VERSION 5.7 ;
  NOWIREEXTENSIONATPIN ON ;
  DIVIDERCHAR "/" ;
  BUSBITCHARS "[]" ;
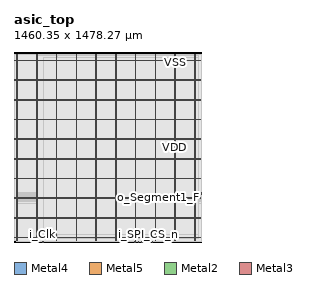
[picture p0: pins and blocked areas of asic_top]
MACRO asic_top
  CLASS BLOCK ;
  FOREIGN asic_top ;
  ORIGIN 0.000 0.000 ;
  SIZE 1460.350 BY 1478.270 ;
  PIN VDD
    DIRECTION INOUT ;
    USE POWER ;
    PORT
      LAYER Metal4 ;
        RECT 22.240 15.380 23.840 1462.460 ;
    END
    PORT
      LAYER Metal4 ;
        RECT 175.840 15.380 177.440 1462.460 ;
    END
    PORT
      LAYER Metal4 ;
        RECT 329.440 15.380 331.040 1462.460 ;
    END
    PORT
      LAYER Metal4 ;
        RECT 483.040 15.380 484.640 1462.460 ;
    END
    PORT
      LAYER Metal4 ;
        RECT 636.640 15.380 638.240 1462.460 ;
    END
    PORT
      LAYER Metal4 ;
        RECT 790.240 15.380 791.840 1462.460 ;
    END
    PORT
      LAYER Metal4 ;
        RECT 943.840 15.380 945.440 1462.460 ;
    END
    PORT
      LAYER Metal4 ;
        RECT 1097.440 15.380 1099.040 1462.460 ;
    END
    PORT
      LAYER Metal4 ;
        RECT 1251.040 15.380 1252.640 1462.460 ;
    END
    PORT
      LAYER Metal4 ;
        RECT 1404.640 15.380 1406.240 1462.460 ;
    END
    PORT
      LAYER Metal5 ;
        RECT 6.720 31.530 1453.200 33.130 ;
    END
    PORT
      LAYER Metal5 ;
        RECT 6.720 184.710 1453.200 186.310 ;
    END
    PORT
      LAYER Metal5 ;
        RECT 6.720 337.890 1453.200 339.490 ;
    END
    PORT
      LAYER Metal5 ;
        RECT 6.720 491.070 1453.200 492.670 ;
    END
    PORT
      LAYER Metal5 ;
        RECT 6.720 644.250 1453.200 645.850 ;
    END
    PORT
      LAYER Metal5 ;
        RECT 6.720 797.430 1453.200 799.030 ;
    END
    PORT
      LAYER Metal5 ;
        RECT 6.720 950.610 1453.200 952.210 ;
    END
    PORT
      LAYER Metal5 ;
        RECT 6.720 1103.790 1453.200 1105.390 ;
    END
    PORT
      LAYER Metal5 ;
        RECT 6.720 1256.970 1453.200 1258.570 ;
    END
    PORT
      LAYER Metal5 ;
        RECT 6.720 1410.150 1453.200 1411.750 ;
    END
  END VDD
  PIN VSS
    DIRECTION INOUT ;
    USE GROUND ;
    PORT
      LAYER Metal4 ;
        RECT 25.540 15.380 27.140 1462.460 ;
    END
    PORT
      LAYER Metal4 ;
        RECT 179.140 15.380 180.740 1462.460 ;
    END
    PORT
      LAYER Metal4 ;
        RECT 332.740 15.380 334.340 1462.460 ;
    END
    PORT
      LAYER Metal4 ;
        RECT 486.340 15.380 487.940 1462.460 ;
    END
    PORT
      LAYER Metal4 ;
        RECT 639.940 15.380 641.540 1462.460 ;
    END
    PORT
      LAYER Metal4 ;
        RECT 793.540 15.380 795.140 1462.460 ;
    END
    PORT
      LAYER Metal4 ;
        RECT 947.140 15.380 948.740 1462.460 ;
    END
    PORT
      LAYER Metal4 ;
        RECT 1100.740 15.380 1102.340 1462.460 ;
    END
    PORT
      LAYER Metal4 ;
        RECT 1254.340 15.380 1255.940 1462.460 ;
    END
    PORT
      LAYER Metal4 ;
        RECT 1407.940 15.380 1409.540 1462.460 ;
    END
    PORT
      LAYER Metal5 ;
        RECT 6.720 34.830 1453.200 36.430 ;
    END
    PORT
      LAYER Metal5 ;
        RECT 6.720 188.010 1453.200 189.610 ;
    END
    PORT
      LAYER Metal5 ;
        RECT 6.720 341.190 1453.200 342.790 ;
    END
    PORT
      LAYER Metal5 ;
        RECT 6.720 494.370 1453.200 495.970 ;
    END
    PORT
      LAYER Metal5 ;
        RECT 6.720 647.550 1453.200 649.150 ;
    END
    PORT
      LAYER Metal5 ;
        RECT 6.720 800.730 1453.200 802.330 ;
    END
    PORT
      LAYER Metal5 ;
        RECT 6.720 953.910 1453.200 955.510 ;
    END
    PORT
      LAYER Metal5 ;
        RECT 6.720 1107.090 1453.200 1108.690 ;
    END
    PORT
      LAYER Metal5 ;
        RECT 6.720 1260.270 1453.200 1261.870 ;
    END
    PORT
      LAYER Metal5 ;
        RECT 6.720 1413.450 1453.200 1415.050 ;
    END
  END VSS
  PIN i_Clk
    DIRECTION INPUT ;
    USE SIGNAL ;
    ANTENNAGATEAREA 4.738000 ;
    PORT
      LAYER Metal2 ;
        RECT 225.120 0.000 225.680 0.560 ;
    END
  END i_Clk
  PIN i_SPI_CS_n
    DIRECTION INPUT ;
    USE SIGNAL ;
    ANTENNAGATEAREA 0.396000 ;
    PORT
      LAYER Metal2 ;
        RECT 1047.200 0.000 1047.760 0.560 ;
    END
  END i_SPI_CS_n
  PIN i_SPI_MOSI
    DIRECTION INPUT ;
    USE SIGNAL ;
    ANTENNAGATEAREA 0.396000 ;
    PORT
      LAYER Metal2 ;
        RECT 943.040 0.000 943.600 0.560 ;
    END
  END i_SPI_MOSI
  PIN i_SPI_SCLK
    DIRECTION INPUT ;
    USE SIGNAL ;
    ANTENNAGATEAREA 0.396000 ;
    PORT
      LAYER Metal2 ;
        RECT 1078.560 0.000 1079.120 0.560 ;
    END
  END i_SPI_SCLK
  PIN i_Switch[0]
    DIRECTION INPUT ;
    USE SIGNAL ;
    ANTENNAGATEAREA 0.396000 ;
    PORT
      LAYER Metal2 ;
        RECT 947.520 0.000 948.080 0.560 ;
    END
  END i_Switch[0]
  PIN i_Switch[1]
    DIRECTION INPUT ;
    USE SIGNAL ;
    ANTENNAGATEAREA 0.396000 ;
    PORT
      LAYER Metal2 ;
        RECT 967.680 0.000 968.240 0.560 ;
    END
  END i_Switch[1]
  PIN i_Switch[2]
    DIRECTION INPUT ;
    USE SIGNAL ;
    ANTENNAGATEAREA 0.396000 ;
    PORT
      LAYER Metal2 ;
        RECT 991.200 0.000 991.760 0.560 ;
    END
  END i_Switch[2]
  PIN i_Switch[3]
    DIRECTION INPUT ;
    USE SIGNAL ;
    ANTENNAGATEAREA 0.396000 ;
    PORT
      LAYER Metal2 ;
        RECT 934.080 0.000 934.640 0.560 ;
    END
  END i_Switch[3]
  PIN o_LED[0]
    DIRECTION OUTPUT ;
    USE SIGNAL ;
    ANTENNADIFFAREA 0.897600 ;
    PORT
      LAYER Metal3 ;
        RECT 1459.790 339.360 1460.350 339.920 ;
    END
  END o_LED[0]
  PIN o_LED[1]
    DIRECTION OUTPUT ;
    USE SIGNAL ;
    ANTENNADIFFAREA 0.897600 ;
    PORT
      LAYER Metal3 ;
        RECT 1459.790 372.960 1460.350 373.520 ;
    END
  END o_LED[1]
  PIN o_LED[2]
    DIRECTION OUTPUT ;
    USE SIGNAL ;
    ANTENNADIFFAREA 0.897600 ;
    PORT
      LAYER Metal3 ;
        RECT 1459.790 362.880 1460.350 363.440 ;
    END
  END o_LED[2]
  PIN o_LED[3]
    DIRECTION OUTPUT ;
    USE SIGNAL ;
    ANTENNADIFFAREA 0.897600 ;
    PORT
      LAYER Metal3 ;
        RECT 1459.790 355.040 1460.350 355.600 ;
    END
  END o_LED[3]
  PIN o_SPI_MISO
    DIRECTION OUTPUT ;
    USE SIGNAL ;
    ANTENNADIFFAREA 0.897600 ;
    PORT
      LAYER Metal3 ;
        RECT 1459.790 302.400 1460.350 302.960 ;
    END
  END o_SPI_MISO
  PIN o_Segment1_A
    DIRECTION OUTPUT ;
    USE SIGNAL ;
    ANTENNADIFFAREA 0.897600 ;
    PORT
      LAYER Metal3 ;
        RECT 1459.790 319.200 1460.350 319.760 ;
    END
  END o_Segment1_A
  PIN o_Segment1_B
    DIRECTION OUTPUT ;
    USE SIGNAL ;
    ANTENNADIFFAREA 0.897600 ;
    PORT
      LAYER Metal3 ;
        RECT 1459.790 337.120 1460.350 337.680 ;
    END
  END o_Segment1_B
  PIN o_Segment1_C
    DIRECTION OUTPUT ;
    USE SIGNAL ;
    ANTENNADIFFAREA 0.897600 ;
    PORT
      LAYER Metal3 ;
        RECT 1459.790 320.320 1460.350 320.880 ;
    END
  END o_Segment1_C
  PIN o_Segment1_D
    DIRECTION OUTPUT ;
    USE SIGNAL ;
    ANTENNADIFFAREA 0.897600 ;
    PORT
      LAYER Metal3 ;
        RECT 1459.790 328.160 1460.350 328.720 ;
    END
  END o_Segment1_D
  PIN o_Segment1_E
    DIRECTION OUTPUT ;
    USE SIGNAL ;
    ANTENNADIFFAREA 0.897600 ;
    PORT
      LAYER Metal3 ;
        RECT 1459.790 315.840 1460.350 316.400 ;
    END
  END o_Segment1_E
  PIN o_Segment1_F
    DIRECTION OUTPUT ;
    USE SIGNAL ;
    ANTENNADIFFAREA 0.897600 ;
    PORT
      LAYER Metal3 ;
        RECT 1459.790 342.720 1460.350 343.280 ;
    END
  END o_Segment1_F
  PIN o_Segment1_G
    DIRECTION OUTPUT ;
    USE SIGNAL ;
    ANTENNADIFFAREA 0.897600 ;
    PORT
      LAYER Metal3 ;
        RECT 1459.790 346.080 1460.350 346.640 ;
    END
  END o_Segment1_G
  PIN o_Segment2_A
    DIRECTION OUTPUT ;
    USE SIGNAL ;
    ANTENNADIFFAREA 0.897600 ;
    PORT
      LAYER Metal3 ;
        RECT 1459.790 351.680 1460.350 352.240 ;
    END
  END o_Segment2_A
  PIN o_Segment2_B
    DIRECTION OUTPUT ;
    USE SIGNAL ;
    ANTENNADIFFAREA 0.897600 ;
    PORT
      LAYER Metal3 ;
        RECT 1459.790 371.840 1460.350 372.400 ;
    END
  END o_Segment2_B
  PIN o_Segment2_C
    DIRECTION OUTPUT ;
    USE SIGNAL ;
    ANTENNADIFFAREA 0.897600 ;
    PORT
      LAYER Metal3 ;
        RECT 1459.790 353.920 1460.350 354.480 ;
    END
  END o_Segment2_C
  PIN o_Segment2_D
    DIRECTION OUTPUT ;
    USE SIGNAL ;
    ANTENNADIFFAREA 0.897600 ;
    PORT
      LAYER Metal3 ;
        RECT 1459.790 361.760 1460.350 362.320 ;
    END
  END o_Segment2_D
  PIN o_Segment2_E
    DIRECTION OUTPUT ;
    USE SIGNAL ;
    ANTENNADIFFAREA 0.897600 ;
    PORT
      LAYER Metal3 ;
        RECT 1459.790 343.840 1460.350 344.400 ;
    END
  END o_Segment2_E
  PIN o_Segment2_F
    DIRECTION OUTPUT ;
    USE SIGNAL ;
    ANTENNADIFFAREA 0.897600 ;
    PORT
      LAYER Metal3 ;
        RECT 1459.790 380.800 1460.350 381.360 ;
    END
  END o_Segment2_F
  PIN o_Segment2_G
    DIRECTION OUTPUT ;
    USE SIGNAL ;
    ANTENNADIFFAREA 0.897600 ;
    PORT
      LAYER Metal3 ;
        RECT 1459.790 377.440 1460.350 378.000 ;
    END
  END o_Segment2_G
  PIN rst_ni
    DIRECTION INPUT ;
    USE SIGNAL ;
    ANTENNAGATEAREA 0.396000 ;
    PORT
      LAYER Metal2 ;
        RECT 226.240 0.000 226.800 0.560 ;
    END
  END rst_ni
  OBS
      LAYER Nwell ;
        RECT 6.290 1460.000 1453.630 1462.590 ;
      LAYER Pwell ;
        RECT 6.290 1456.480 1453.630 1460.000 ;
      LAYER Nwell ;
        RECT 6.290 1452.160 1453.630 1456.480 ;
      LAYER Pwell ;
        RECT 6.290 1448.640 1453.630 1452.160 ;
      LAYER Nwell ;
        RECT 6.290 1444.320 1453.630 1448.640 ;
      LAYER Pwell ;
        RECT 6.290 1440.800 1453.630 1444.320 ;
      LAYER Nwell ;
        RECT 6.290 1436.480 1453.630 1440.800 ;
      LAYER Pwell ;
        RECT 6.290 1432.960 1453.630 1436.480 ;
      LAYER Nwell ;
        RECT 6.290 1428.640 1453.630 1432.960 ;
      LAYER Pwell ;
        RECT 6.290 1425.120 1453.630 1428.640 ;
      LAYER Nwell ;
        RECT 6.290 1420.800 1453.630 1425.120 ;
      LAYER Pwell ;
        RECT 6.290 1417.280 1453.630 1420.800 ;
      LAYER Nwell ;
        RECT 6.290 1412.960 1453.630 1417.280 ;
      LAYER Pwell ;
        RECT 6.290 1409.440 1453.630 1412.960 ;
      LAYER Nwell ;
        RECT 6.290 1405.120 1453.630 1409.440 ;
      LAYER Pwell ;
        RECT 6.290 1401.600 1453.630 1405.120 ;
      LAYER Nwell ;
        RECT 6.290 1397.280 1453.630 1401.600 ;
      LAYER Pwell ;
        RECT 6.290 1393.760 1453.630 1397.280 ;
      LAYER Nwell ;
        RECT 6.290 1389.440 1453.630 1393.760 ;
      LAYER Pwell ;
        RECT 6.290 1385.920 1453.630 1389.440 ;
      LAYER Nwell ;
        RECT 6.290 1381.600 1453.630 1385.920 ;
      LAYER Pwell ;
        RECT 6.290 1378.080 1453.630 1381.600 ;
      LAYER Nwell ;
        RECT 6.290 1373.760 1453.630 1378.080 ;
      LAYER Pwell ;
        RECT 6.290 1370.240 1453.630 1373.760 ;
      LAYER Nwell ;
        RECT 6.290 1365.920 1453.630 1370.240 ;
      LAYER Pwell ;
        RECT 6.290 1362.400 1453.630 1365.920 ;
      LAYER Nwell ;
        RECT 6.290 1358.080 1453.630 1362.400 ;
      LAYER Pwell ;
        RECT 6.290 1354.560 1453.630 1358.080 ;
      LAYER Nwell ;
        RECT 6.290 1350.240 1453.630 1354.560 ;
      LAYER Pwell ;
        RECT 6.290 1346.720 1453.630 1350.240 ;
      LAYER Nwell ;
        RECT 6.290 1342.400 1453.630 1346.720 ;
      LAYER Pwell ;
        RECT 6.290 1338.880 1453.630 1342.400 ;
      LAYER Nwell ;
        RECT 6.290 1334.560 1453.630 1338.880 ;
      LAYER Pwell ;
        RECT 6.290 1331.040 1453.630 1334.560 ;
      LAYER Nwell ;
        RECT 6.290 1326.720 1453.630 1331.040 ;
      LAYER Pwell ;
        RECT 6.290 1323.200 1453.630 1326.720 ;
      LAYER Nwell ;
        RECT 6.290 1318.880 1453.630 1323.200 ;
      LAYER Pwell ;
        RECT 6.290 1315.360 1453.630 1318.880 ;
      LAYER Nwell ;
        RECT 6.290 1311.040 1453.630 1315.360 ;
      LAYER Pwell ;
        RECT 6.290 1307.520 1453.630 1311.040 ;
      LAYER Nwell ;
        RECT 6.290 1303.200 1453.630 1307.520 ;
      LAYER Pwell ;
        RECT 6.290 1299.680 1453.630 1303.200 ;
      LAYER Nwell ;
        RECT 6.290 1295.360 1453.630 1299.680 ;
      LAYER Pwell ;
        RECT 6.290 1291.840 1453.630 1295.360 ;
      LAYER Nwell ;
        RECT 6.290 1287.520 1453.630 1291.840 ;
      LAYER Pwell ;
        RECT 6.290 1284.000 1453.630 1287.520 ;
      LAYER Nwell ;
        RECT 6.290 1279.680 1453.630 1284.000 ;
      LAYER Pwell ;
        RECT 6.290 1276.160 1453.630 1279.680 ;
      LAYER Nwell ;
        RECT 6.290 1271.840 1453.630 1276.160 ;
      LAYER Pwell ;
        RECT 6.290 1268.320 1453.630 1271.840 ;
      LAYER Nwell ;
        RECT 6.290 1264.000 1453.630 1268.320 ;
      LAYER Pwell ;
        RECT 6.290 1261.810 1453.630 1264.000 ;
        RECT 6.290 1260.480 421.550 1261.810 ;
      LAYER Nwell ;
        RECT 421.550 1260.480 1453.630 1261.810 ;
        RECT 6.290 1256.160 1453.630 1260.480 ;
      LAYER Pwell ;
        RECT 6.290 1253.970 1453.630 1256.160 ;
        RECT 6.290 1252.640 1027.470 1253.970 ;
      LAYER Nwell ;
        RECT 1027.470 1252.640 1453.630 1253.970 ;
        RECT 6.290 1248.320 1453.630 1252.640 ;
      LAYER Pwell ;
        RECT 6.290 1244.800 1453.630 1248.320 ;
      LAYER Nwell ;
        RECT 6.290 1240.480 1453.630 1244.800 ;
      LAYER Pwell ;
        RECT 6.290 1236.960 1453.630 1240.480 ;
      LAYER Nwell ;
        RECT 6.290 1232.640 1453.630 1236.960 ;
      LAYER Pwell ;
        RECT 6.290 1229.120 1453.630 1232.640 ;
      LAYER Nwell ;
        RECT 6.290 1224.800 1453.630 1229.120 ;
      LAYER Pwell ;
        RECT 6.290 1221.280 1453.630 1224.800 ;
      LAYER Nwell ;
        RECT 6.290 1216.960 1453.630 1221.280 ;
      LAYER Pwell ;
        RECT 6.290 1213.440 1453.630 1216.960 ;
      LAYER Nwell ;
        RECT 6.290 1209.120 1453.630 1213.440 ;
      LAYER Pwell ;
        RECT 6.290 1205.600 1453.630 1209.120 ;
      LAYER Nwell ;
        RECT 6.290 1201.280 1453.630 1205.600 ;
      LAYER Pwell ;
        RECT 6.290 1197.760 1453.630 1201.280 ;
      LAYER Nwell ;
        RECT 6.290 1193.440 1453.630 1197.760 ;
      LAYER Pwell ;
        RECT 6.290 1189.920 1453.630 1193.440 ;
      LAYER Nwell ;
        RECT 6.290 1185.600 1453.630 1189.920 ;
      LAYER Pwell ;
        RECT 6.290 1183.410 1453.630 1185.600 ;
        RECT 6.290 1182.080 763.710 1183.410 ;
      LAYER Nwell ;
        RECT 763.710 1182.080 1453.630 1183.410 ;
        RECT 6.290 1177.760 1453.630 1182.080 ;
      LAYER Pwell ;
        RECT 6.290 1174.240 1453.630 1177.760 ;
      LAYER Nwell ;
        RECT 6.290 1169.920 1453.630 1174.240 ;
      LAYER Pwell ;
        RECT 6.290 1166.400 1453.630 1169.920 ;
      LAYER Nwell ;
        RECT 6.290 1162.080 1453.630 1166.400 ;
      LAYER Pwell ;
        RECT 6.290 1158.560 1453.630 1162.080 ;
      LAYER Nwell ;
        RECT 6.290 1154.240 1453.630 1158.560 ;
      LAYER Pwell ;
        RECT 6.290 1150.720 1453.630 1154.240 ;
      LAYER Nwell ;
        RECT 6.290 1146.400 1453.630 1150.720 ;
      LAYER Pwell ;
        RECT 6.290 1142.880 1453.630 1146.400 ;
      LAYER Nwell ;
        RECT 6.290 1138.560 1453.630 1142.880 ;
      LAYER Pwell ;
        RECT 6.290 1135.040 1453.630 1138.560 ;
      LAYER Nwell ;
        RECT 6.290 1130.720 1453.630 1135.040 ;
      LAYER Pwell ;
        RECT 6.290 1128.530 1453.630 1130.720 ;
        RECT 6.290 1127.200 1145.630 1128.530 ;
      LAYER Nwell ;
        RECT 1145.630 1127.200 1453.630 1128.530 ;
        RECT 6.290 1122.880 1453.630 1127.200 ;
      LAYER Pwell ;
        RECT 6.290 1119.360 1453.630 1122.880 ;
      LAYER Nwell ;
        RECT 6.290 1115.040 1453.630 1119.360 ;
      LAYER Pwell ;
        RECT 6.290 1111.520 1453.630 1115.040 ;
      LAYER Nwell ;
        RECT 6.290 1107.200 1453.630 1111.520 ;
      LAYER Pwell ;
        RECT 6.290 1103.680 1453.630 1107.200 ;
      LAYER Nwell ;
        RECT 6.290 1099.360 1453.630 1103.680 ;
      LAYER Pwell ;
        RECT 6.290 1097.170 1453.630 1099.360 ;
        RECT 6.290 1095.840 560.430 1097.170 ;
      LAYER Nwell ;
        RECT 560.430 1095.840 1453.630 1097.170 ;
        RECT 6.290 1091.520 1453.630 1095.840 ;
      LAYER Pwell ;
        RECT 6.290 1088.000 1453.630 1091.520 ;
      LAYER Nwell ;
        RECT 6.290 1083.680 1453.630 1088.000 ;
      LAYER Pwell ;
        RECT 6.290 1080.160 1453.630 1083.680 ;
      LAYER Nwell ;
        RECT 6.290 1075.840 1453.630 1080.160 ;
      LAYER Pwell ;
        RECT 6.290 1072.320 1453.630 1075.840 ;
      LAYER Nwell ;
        RECT 6.290 1068.000 1453.630 1072.320 ;
      LAYER Pwell ;
        RECT 6.290 1064.480 1453.630 1068.000 ;
      LAYER Nwell ;
        RECT 6.290 1060.160 1453.630 1064.480 ;
      LAYER Pwell ;
        RECT 6.290 1057.970 1453.630 1060.160 ;
        RECT 6.290 1056.640 961.950 1057.970 ;
      LAYER Nwell ;
        RECT 961.950 1056.640 1453.630 1057.970 ;
        RECT 6.290 1052.320 1453.630 1056.640 ;
      LAYER Pwell ;
        RECT 6.290 1050.130 1453.630 1052.320 ;
        RECT 6.290 1048.800 724.510 1050.130 ;
      LAYER Nwell ;
        RECT 724.510 1048.800 1453.630 1050.130 ;
        RECT 6.290 1044.480 1453.630 1048.800 ;
      LAYER Pwell ;
        RECT 6.290 1040.960 1453.630 1044.480 ;
      LAYER Nwell ;
        RECT 6.290 1036.640 1453.630 1040.960 ;
      LAYER Pwell ;
        RECT 6.290 1034.450 1453.630 1036.640 ;
        RECT 6.290 1033.120 960.270 1034.450 ;
      LAYER Nwell ;
        RECT 960.270 1033.120 1453.630 1034.450 ;
        RECT 6.290 1028.800 1453.630 1033.120 ;
      LAYER Pwell ;
        RECT 6.290 1025.280 1453.630 1028.800 ;
      LAYER Nwell ;
        RECT 6.290 1020.960 1453.630 1025.280 ;
      LAYER Pwell ;
        RECT 6.290 1018.770 1453.630 1020.960 ;
        RECT 6.290 1017.440 1081.790 1018.770 ;
      LAYER Nwell ;
        RECT 1081.790 1017.440 1453.630 1018.770 ;
        RECT 6.290 1013.120 1453.630 1017.440 ;
      LAYER Pwell ;
        RECT 6.290 1009.600 1453.630 1013.120 ;
      LAYER Nwell ;
        RECT 6.290 1005.280 1453.630 1009.600 ;
      LAYER Pwell ;
        RECT 6.290 1003.090 1453.630 1005.280 ;
        RECT 6.290 1001.760 940.110 1003.090 ;
      LAYER Nwell ;
        RECT 940.110 1001.760 1453.630 1003.090 ;
        RECT 6.290 997.440 1453.630 1001.760 ;
      LAYER Pwell ;
        RECT 6.290 995.250 1453.630 997.440 ;
        RECT 6.290 993.920 1066.670 995.250 ;
      LAYER Nwell ;
        RECT 1066.670 993.920 1453.630 995.250 ;
        RECT 6.290 989.600 1453.630 993.920 ;
      LAYER Pwell ;
        RECT 6.290 986.080 1453.630 989.600 ;
      LAYER Nwell ;
        RECT 6.290 981.760 1453.630 986.080 ;
      LAYER Pwell ;
        RECT 6.290 978.240 1453.630 981.760 ;
      LAYER Nwell ;
        RECT 6.290 973.920 1453.630 978.240 ;
      LAYER Pwell ;
        RECT 6.290 971.730 1453.630 973.920 ;
        RECT 6.290 970.400 1262.670 971.730 ;
      LAYER Nwell ;
        RECT 1262.670 970.400 1453.630 971.730 ;
        RECT 6.290 966.080 1453.630 970.400 ;
      LAYER Pwell ;
        RECT 6.290 962.560 1453.630 966.080 ;
      LAYER Nwell ;
        RECT 6.290 958.240 1453.630 962.560 ;
      LAYER Pwell ;
        RECT 6.290 954.720 1453.630 958.240 ;
      LAYER Nwell ;
        RECT 6.290 950.400 1453.630 954.720 ;
      LAYER Pwell ;
        RECT 6.290 946.880 1453.630 950.400 ;
      LAYER Nwell ;
        RECT 6.290 942.560 1453.630 946.880 ;
      LAYER Pwell ;
        RECT 6.290 940.370 1453.630 942.560 ;
        RECT 6.290 939.040 693.150 940.370 ;
      LAYER Nwell ;
        RECT 693.150 939.040 1453.630 940.370 ;
        RECT 6.290 934.720 1453.630 939.040 ;
      LAYER Pwell ;
        RECT 6.290 931.200 1453.630 934.720 ;
      LAYER Nwell ;
        RECT 6.290 926.880 1453.630 931.200 ;
      LAYER Pwell ;
        RECT 6.290 924.690 1453.630 926.880 ;
        RECT 6.290 923.360 569.390 924.690 ;
      LAYER Nwell ;
        RECT 569.390 923.360 1453.630 924.690 ;
        RECT 6.290 919.040 1453.630 923.360 ;
      LAYER Pwell ;
        RECT 6.290 915.520 1453.630 919.040 ;
      LAYER Nwell ;
        RECT 6.290 911.200 1453.630 915.520 ;
      LAYER Pwell ;
        RECT 6.290 907.680 1453.630 911.200 ;
      LAYER Nwell ;
        RECT 6.290 903.360 1453.630 907.680 ;
      LAYER Pwell ;
        RECT 6.290 899.840 1453.630 903.360 ;
      LAYER Nwell ;
        RECT 6.290 895.520 1453.630 899.840 ;
      LAYER Pwell ;
        RECT 6.290 892.000 1453.630 895.520 ;
      LAYER Nwell ;
        RECT 6.290 887.680 1453.630 892.000 ;
      LAYER Pwell ;
        RECT 6.290 884.160 1453.630 887.680 ;
      LAYER Nwell ;
        RECT 6.290 879.840 1453.630 884.160 ;
      LAYER Pwell ;
        RECT 6.290 876.320 1453.630 879.840 ;
      LAYER Nwell ;
        RECT 6.290 872.000 1453.630 876.320 ;
      LAYER Pwell ;
        RECT 6.290 868.480 1453.630 872.000 ;
      LAYER Nwell ;
        RECT 6.290 864.160 1453.630 868.480 ;
      LAYER Pwell ;
        RECT 6.290 861.970 1453.630 864.160 ;
        RECT 6.290 860.640 674.670 861.970 ;
      LAYER Nwell ;
        RECT 674.670 860.640 1453.630 861.970 ;
        RECT 6.290 856.320 1453.630 860.640 ;
      LAYER Pwell ;
        RECT 6.290 852.800 1453.630 856.320 ;
      LAYER Nwell ;
        RECT 6.290 848.480 1453.630 852.800 ;
      LAYER Pwell ;
        RECT 6.290 844.960 1453.630 848.480 ;
      LAYER Nwell ;
        RECT 6.290 840.640 1453.630 844.960 ;
      LAYER Pwell ;
        RECT 6.290 838.450 1453.630 840.640 ;
        RECT 6.290 837.120 917.710 838.450 ;
      LAYER Nwell ;
        RECT 917.710 837.120 1453.630 838.450 ;
        RECT 6.290 832.800 1453.630 837.120 ;
      LAYER Pwell ;
        RECT 6.290 829.280 1453.630 832.800 ;
      LAYER Nwell ;
        RECT 6.290 824.960 1453.630 829.280 ;
      LAYER Pwell ;
        RECT 6.290 822.770 1453.630 824.960 ;
        RECT 6.290 821.440 1002.270 822.770 ;
      LAYER Nwell ;
        RECT 1002.270 821.440 1453.630 822.770 ;
        RECT 6.290 817.120 1453.630 821.440 ;
      LAYER Pwell ;
        RECT 6.290 813.600 1453.630 817.120 ;
      LAYER Nwell ;
        RECT 6.290 809.280 1453.630 813.600 ;
      LAYER Pwell ;
        RECT 6.290 805.760 1453.630 809.280 ;
      LAYER Nwell ;
        RECT 6.290 801.440 1453.630 805.760 ;
      LAYER Pwell ;
        RECT 6.290 797.920 1453.630 801.440 ;
      LAYER Nwell ;
        RECT 6.290 793.600 1453.630 797.920 ;
      LAYER Pwell ;
        RECT 6.290 791.410 1453.630 793.600 ;
        RECT 6.290 790.080 674.670 791.410 ;
      LAYER Nwell ;
        RECT 674.670 790.080 1453.630 791.410 ;
        RECT 6.290 785.760 1453.630 790.080 ;
      LAYER Pwell ;
        RECT 6.290 782.240 1453.630 785.760 ;
      LAYER Nwell ;
        RECT 6.290 777.920 1453.630 782.240 ;
      LAYER Pwell ;
        RECT 6.290 774.400 1453.630 777.920 ;
      LAYER Nwell ;
        RECT 6.290 770.080 1453.630 774.400 ;
      LAYER Pwell ;
        RECT 6.290 766.560 1453.630 770.080 ;
      LAYER Nwell ;
        RECT 6.290 762.240 1453.630 766.560 ;
      LAYER Pwell ;
        RECT 6.290 758.720 1453.630 762.240 ;
      LAYER Nwell ;
        RECT 6.290 754.400 1453.630 758.720 ;
      LAYER Pwell ;
        RECT 6.290 750.880 1453.630 754.400 ;
      LAYER Nwell ;
        RECT 6.290 746.560 1453.630 750.880 ;
      LAYER Pwell ;
        RECT 6.290 744.370 1453.630 746.560 ;
        RECT 6.290 743.040 940.110 744.370 ;
      LAYER Nwell ;
        RECT 940.110 743.040 1453.630 744.370 ;
        RECT 6.290 738.720 1453.630 743.040 ;
      LAYER Pwell ;
        RECT 6.290 735.200 1453.630 738.720 ;
      LAYER Nwell ;
        RECT 6.290 730.880 1453.630 735.200 ;
      LAYER Pwell ;
        RECT 6.290 727.360 1453.630 730.880 ;
      LAYER Nwell ;
        RECT 6.290 723.040 1453.630 727.360 ;
      LAYER Pwell ;
        RECT 6.290 719.520 1453.630 723.040 ;
      LAYER Nwell ;
        RECT 6.290 715.200 1453.630 719.520 ;
      LAYER Pwell ;
        RECT 6.290 711.680 1453.630 715.200 ;
      LAYER Nwell ;
        RECT 6.290 707.360 1453.630 711.680 ;
      LAYER Pwell ;
        RECT 6.290 705.170 1453.630 707.360 ;
        RECT 6.290 703.840 848.270 705.170 ;
      LAYER Nwell ;
        RECT 848.270 703.840 1453.630 705.170 ;
        RECT 6.290 699.520 1453.630 703.840 ;
      LAYER Pwell ;
        RECT 6.290 696.000 1453.630 699.520 ;
      LAYER Nwell ;
        RECT 6.290 691.680 1453.630 696.000 ;
      LAYER Pwell ;
        RECT 6.290 688.160 1453.630 691.680 ;
      LAYER Nwell ;
        RECT 6.290 683.840 1453.630 688.160 ;
      LAYER Pwell ;
        RECT 6.290 680.320 1453.630 683.840 ;
      LAYER Nwell ;
        RECT 6.290 676.000 1453.630 680.320 ;
      LAYER Pwell ;
        RECT 6.290 672.480 1453.630 676.000 ;
      LAYER Nwell ;
        RECT 6.290 668.160 1453.630 672.480 ;
      LAYER Pwell ;
        RECT 6.290 665.970 1453.630 668.160 ;
        RECT 6.290 664.640 1066.670 665.970 ;
      LAYER Nwell ;
        RECT 1066.670 664.640 1453.630 665.970 ;
        RECT 6.290 660.320 1453.630 664.640 ;
      LAYER Pwell ;
        RECT 6.290 656.800 1453.630 660.320 ;
      LAYER Nwell ;
        RECT 6.290 652.480 1453.630 656.800 ;
      LAYER Pwell ;
        RECT 6.290 650.290 1453.630 652.480 ;
        RECT 6.290 648.960 953.550 650.290 ;
      LAYER Nwell ;
        RECT 953.550 648.960 1453.630 650.290 ;
        RECT 6.290 644.640 1453.630 648.960 ;
      LAYER Pwell ;
        RECT 6.290 641.120 1453.630 644.640 ;
      LAYER Nwell ;
        RECT 6.290 636.800 1453.630 641.120 ;
      LAYER Pwell ;
        RECT 6.290 634.610 1453.630 636.800 ;
        RECT 6.290 633.280 766.510 634.610 ;
      LAYER Nwell ;
        RECT 766.510 633.280 1453.630 634.610 ;
        RECT 6.290 628.960 1453.630 633.280 ;
      LAYER Pwell ;
        RECT 6.290 626.770 1453.630 628.960 ;
        RECT 6.290 625.440 1012.910 626.770 ;
      LAYER Nwell ;
        RECT 1012.910 625.440 1453.630 626.770 ;
        RECT 6.290 621.120 1453.630 625.440 ;
      LAYER Pwell ;
        RECT 6.290 617.600 1453.630 621.120 ;
      LAYER Nwell ;
        RECT 6.290 613.280 1453.630 617.600 ;
      LAYER Pwell ;
        RECT 6.290 609.760 1453.630 613.280 ;
      LAYER Nwell ;
        RECT 6.290 605.440 1453.630 609.760 ;
      LAYER Pwell ;
        RECT 6.290 601.920 1453.630 605.440 ;
      LAYER Nwell ;
        RECT 6.290 597.600 1453.630 601.920 ;
      LAYER Pwell ;
        RECT 6.290 595.410 1453.630 597.600 ;
        RECT 6.290 594.080 1014.030 595.410 ;
      LAYER Nwell ;
        RECT 1014.030 594.080 1453.630 595.410 ;
        RECT 6.290 589.760 1453.630 594.080 ;
      LAYER Pwell ;
        RECT 6.290 587.570 1453.630 589.760 ;
        RECT 6.290 586.240 881.870 587.570 ;
      LAYER Nwell ;
        RECT 881.870 586.240 1453.630 587.570 ;
        RECT 6.290 581.920 1453.630 586.240 ;
      LAYER Pwell ;
        RECT 6.290 578.400 1453.630 581.920 ;
      LAYER Nwell ;
        RECT 6.290 574.080 1453.630 578.400 ;
      LAYER Pwell ;
        RECT 6.290 570.560 1453.630 574.080 ;
      LAYER Nwell ;
        RECT 6.290 566.240 1453.630 570.560 ;
      LAYER Pwell ;
        RECT 6.290 562.720 1453.630 566.240 ;
      LAYER Nwell ;
        RECT 6.290 558.400 1453.630 562.720 ;
      LAYER Pwell ;
        RECT 6.290 554.880 1453.630 558.400 ;
      LAYER Nwell ;
        RECT 6.290 550.560 1453.630 554.880 ;
      LAYER Pwell ;
        RECT 6.290 547.040 1453.630 550.560 ;
      LAYER Nwell ;
        RECT 6.290 542.720 1453.630 547.040 ;
      LAYER Pwell ;
        RECT 6.290 539.200 1453.630 542.720 ;
      LAYER Nwell ;
        RECT 6.290 534.880 1453.630 539.200 ;
      LAYER Pwell ;
        RECT 6.290 531.360 1453.630 534.880 ;
      LAYER Nwell ;
        RECT 6.290 527.040 1453.630 531.360 ;
      LAYER Pwell ;
        RECT 6.290 523.520 1453.630 527.040 ;
      LAYER Nwell ;
        RECT 6.290 519.200 1453.630 523.520 ;
      LAYER Pwell ;
        RECT 6.290 515.680 1453.630 519.200 ;
      LAYER Nwell ;
        RECT 6.290 511.360 1453.630 515.680 ;
      LAYER Pwell ;
        RECT 6.290 507.840 1453.630 511.360 ;
      LAYER Nwell ;
        RECT 6.290 503.520 1453.630 507.840 ;
      LAYER Pwell ;
        RECT 6.290 500.000 1453.630 503.520 ;
      LAYER Nwell ;
        RECT 6.290 495.680 1453.630 500.000 ;
      LAYER Pwell ;
        RECT 6.290 492.160 1453.630 495.680 ;
      LAYER Nwell ;
        RECT 6.290 487.840 1453.630 492.160 ;
      LAYER Pwell ;
        RECT 6.290 484.320 1453.630 487.840 ;
      LAYER Nwell ;
        RECT 6.290 480.000 1453.630 484.320 ;
      LAYER Pwell ;
        RECT 6.290 476.480 1453.630 480.000 ;
      LAYER Nwell ;
        RECT 6.290 472.160 1453.630 476.480 ;
      LAYER Pwell ;
        RECT 6.290 468.640 1453.630 472.160 ;
      LAYER Nwell ;
        RECT 6.290 464.320 1453.630 468.640 ;
      LAYER Pwell ;
        RECT 6.290 460.800 1453.630 464.320 ;
      LAYER Nwell ;
        RECT 6.290 456.480 1453.630 460.800 ;
      LAYER Pwell ;
        RECT 6.290 452.960 1453.630 456.480 ;
      LAYER Nwell ;
        RECT 6.290 448.640 1453.630 452.960 ;
      LAYER Pwell ;
        RECT 6.290 445.120 1453.630 448.640 ;
      LAYER Nwell ;
        RECT 6.290 440.800 1453.630 445.120 ;
      LAYER Pwell ;
        RECT 6.290 437.280 1453.630 440.800 ;
      LAYER Nwell ;
        RECT 6.290 432.960 1453.630 437.280 ;
      LAYER Pwell ;
        RECT 6.290 429.440 1453.630 432.960 ;
      LAYER Nwell ;
        RECT 6.290 425.120 1453.630 429.440 ;
      LAYER Pwell ;
        RECT 6.290 421.600 1453.630 425.120 ;
      LAYER Nwell ;
        RECT 6.290 417.280 1453.630 421.600 ;
      LAYER Pwell ;
        RECT 6.290 413.760 1453.630 417.280 ;
      LAYER Nwell ;
        RECT 6.290 409.440 1453.630 413.760 ;
      LAYER Pwell ;
        RECT 6.290 405.920 1453.630 409.440 ;
      LAYER Nwell ;
        RECT 6.290 401.600 1453.630 405.920 ;
      LAYER Pwell ;
        RECT 6.290 398.080 1453.630 401.600 ;
      LAYER Nwell ;
        RECT 6.290 393.760 1453.630 398.080 ;
      LAYER Pwell ;
        RECT 6.290 390.240 1453.630 393.760 ;
      LAYER Nwell ;
        RECT 6.290 385.920 1453.630 390.240 ;
      LAYER Pwell ;
        RECT 6.290 382.400 1453.630 385.920 ;
      LAYER Nwell ;
        RECT 6.290 378.080 1453.630 382.400 ;
      LAYER Pwell ;
        RECT 6.290 374.560 1453.630 378.080 ;
      LAYER Nwell ;
        RECT 6.290 370.240 1453.630 374.560 ;
      LAYER Pwell ;
        RECT 6.290 368.050 1453.630 370.240 ;
        RECT 6.290 366.720 977.070 368.050 ;
      LAYER Nwell ;
        RECT 977.070 366.720 1453.630 368.050 ;
        RECT 6.290 362.400 1453.630 366.720 ;
      LAYER Pwell ;
        RECT 6.290 358.880 1453.630 362.400 ;
      LAYER Nwell ;
        RECT 6.290 354.560 1453.630 358.880 ;
      LAYER Pwell ;
        RECT 6.290 351.040 1453.630 354.560 ;
      LAYER Nwell ;
        RECT 6.290 346.720 1453.630 351.040 ;
      LAYER Pwell ;
        RECT 6.290 343.200 1453.630 346.720 ;
      LAYER Nwell ;
        RECT 6.290 338.880 1453.630 343.200 ;
      LAYER Pwell ;
        RECT 6.290 335.360 1453.630 338.880 ;
      LAYER Nwell ;
        RECT 6.290 331.040 1453.630 335.360 ;
      LAYER Pwell ;
        RECT 6.290 327.520 1453.630 331.040 ;
      LAYER Nwell ;
        RECT 6.290 323.200 1453.630 327.520 ;
      LAYER Pwell ;
        RECT 6.290 319.680 1453.630 323.200 ;
      LAYER Nwell ;
        RECT 6.290 315.360 1453.630 319.680 ;
      LAYER Pwell ;
        RECT 6.290 311.840 1453.630 315.360 ;
      LAYER Nwell ;
        RECT 6.290 307.520 1453.630 311.840 ;
      LAYER Pwell ;
        RECT 6.290 304.000 1453.630 307.520 ;
      LAYER Nwell ;
        RECT 6.290 299.680 1453.630 304.000 ;
      LAYER Pwell ;
        RECT 6.290 296.160 1453.630 299.680 ;
      LAYER Nwell ;
        RECT 6.290 291.840 1453.630 296.160 ;
      LAYER Pwell ;
        RECT 6.290 288.320 1453.630 291.840 ;
      LAYER Nwell ;
        RECT 6.290 284.000 1453.630 288.320 ;
      LAYER Pwell ;
        RECT 6.290 280.480 1453.630 284.000 ;
      LAYER Nwell ;
        RECT 6.290 276.160 1453.630 280.480 ;
      LAYER Pwell ;
        RECT 6.290 272.640 1453.630 276.160 ;
      LAYER Nwell ;
        RECT 6.290 268.320 1453.630 272.640 ;
      LAYER Pwell ;
        RECT 6.290 264.800 1453.630 268.320 ;
      LAYER Nwell ;
        RECT 6.290 260.480 1453.630 264.800 ;
      LAYER Pwell ;
        RECT 6.290 256.960 1453.630 260.480 ;
      LAYER Nwell ;
        RECT 6.290 252.640 1453.630 256.960 ;
      LAYER Pwell ;
        RECT 6.290 249.120 1453.630 252.640 ;
      LAYER Nwell ;
        RECT 6.290 244.800 1453.630 249.120 ;
      LAYER Pwell ;
        RECT 6.290 241.280 1453.630 244.800 ;
      LAYER Nwell ;
        RECT 6.290 236.960 1453.630 241.280 ;
      LAYER Pwell ;
        RECT 6.290 233.440 1453.630 236.960 ;
      LAYER Nwell ;
        RECT 6.290 229.120 1453.630 233.440 ;
      LAYER Pwell ;
        RECT 6.290 225.600 1453.630 229.120 ;
      LAYER Nwell ;
        RECT 6.290 221.280 1453.630 225.600 ;
      LAYER Pwell ;
        RECT 6.290 217.760 1453.630 221.280 ;
      LAYER Nwell ;
        RECT 6.290 213.440 1453.630 217.760 ;
      LAYER Pwell ;
        RECT 6.290 209.920 1453.630 213.440 ;
      LAYER Nwell ;
        RECT 6.290 205.600 1453.630 209.920 ;
      LAYER Pwell ;
        RECT 6.290 202.080 1453.630 205.600 ;
      LAYER Nwell ;
        RECT 6.290 197.760 1453.630 202.080 ;
      LAYER Pwell ;
        RECT 6.290 194.240 1453.630 197.760 ;
      LAYER Nwell ;
        RECT 6.290 189.920 1453.630 194.240 ;
      LAYER Pwell ;
        RECT 6.290 186.400 1453.630 189.920 ;
      LAYER Nwell ;
        RECT 6.290 182.080 1453.630 186.400 ;
      LAYER Pwell ;
        RECT 6.290 178.560 1453.630 182.080 ;
      LAYER Nwell ;
        RECT 6.290 174.240 1453.630 178.560 ;
      LAYER Pwell ;
        RECT 6.290 170.720 1453.630 174.240 ;
      LAYER Nwell ;
        RECT 6.290 166.400 1453.630 170.720 ;
      LAYER Pwell ;
        RECT 6.290 162.880 1453.630 166.400 ;
      LAYER Nwell ;
        RECT 6.290 158.560 1453.630 162.880 ;
      LAYER Pwell ;
        RECT 6.290 155.040 1453.630 158.560 ;
      LAYER Nwell ;
        RECT 6.290 150.720 1453.630 155.040 ;
      LAYER Pwell ;
        RECT 6.290 147.200 1453.630 150.720 ;
      LAYER Nwell ;
        RECT 6.290 142.880 1453.630 147.200 ;
      LAYER Pwell ;
        RECT 6.290 139.360 1453.630 142.880 ;
      LAYER Nwell ;
        RECT 6.290 135.040 1453.630 139.360 ;
      LAYER Pwell ;
        RECT 6.290 131.520 1453.630 135.040 ;
      LAYER Nwell ;
        RECT 6.290 127.200 1453.630 131.520 ;
      LAYER Pwell ;
        RECT 6.290 123.680 1453.630 127.200 ;
      LAYER Nwell ;
        RECT 6.290 119.360 1453.630 123.680 ;
      LAYER Pwell ;
        RECT 6.290 115.840 1453.630 119.360 ;
      LAYER Nwell ;
        RECT 6.290 111.520 1453.630 115.840 ;
      LAYER Pwell ;
        RECT 6.290 108.000 1453.630 111.520 ;
      LAYER Nwell ;
        RECT 6.290 103.680 1453.630 108.000 ;
      LAYER Pwell ;
        RECT 6.290 100.160 1453.630 103.680 ;
      LAYER Nwell ;
        RECT 6.290 95.840 1453.630 100.160 ;
      LAYER Pwell ;
        RECT 6.290 92.320 1453.630 95.840 ;
      LAYER Nwell ;
        RECT 6.290 88.000 1453.630 92.320 ;
      LAYER Pwell ;
        RECT 6.290 84.480 1453.630 88.000 ;
      LAYER Nwell ;
        RECT 6.290 80.160 1453.630 84.480 ;
      LAYER Pwell ;
        RECT 6.290 76.640 1453.630 80.160 ;
      LAYER Nwell ;
        RECT 6.290 72.320 1453.630 76.640 ;
      LAYER Pwell ;
        RECT 6.290 68.800 1453.630 72.320 ;
      LAYER Nwell ;
        RECT 6.290 64.480 1453.630 68.800 ;
      LAYER Pwell ;
        RECT 6.290 60.960 1453.630 64.480 ;
      LAYER Nwell ;
        RECT 6.290 56.640 1453.630 60.960 ;
      LAYER Pwell ;
        RECT 6.290 53.120 1453.630 56.640 ;
      LAYER Nwell ;
        RECT 6.290 48.800 1453.630 53.120 ;
      LAYER Pwell ;
        RECT 6.290 45.280 1453.630 48.800 ;
      LAYER Nwell ;
        RECT 6.290 40.960 1453.630 45.280 ;
      LAYER Pwell ;
        RECT 6.290 37.440 1453.630 40.960 ;
      LAYER Nwell ;
        RECT 6.290 33.120 1453.630 37.440 ;
      LAYER Pwell ;
        RECT 6.290 29.600 1453.630 33.120 ;
      LAYER Nwell ;
        RECT 6.290 25.280 1453.630 29.600 ;
      LAYER Pwell ;
        RECT 6.290 21.760 1453.630 25.280 ;
      LAYER Nwell ;
        RECT 6.290 17.440 1453.630 21.760 ;
      LAYER Pwell ;
        RECT 6.290 15.250 1453.630 17.440 ;
      LAYER Metal1 ;
        RECT 6.720 15.380 1453.200 1462.460 ;
      LAYER Metal2 ;
        RECT 22.380 0.860 1451.380 1462.350 ;
        RECT 22.380 0.090 224.820 0.860 ;
        RECT 227.100 0.090 933.780 0.860 ;
        RECT 934.940 0.090 942.740 0.860 ;
        RECT 943.900 0.090 947.220 0.860 ;
        RECT 948.380 0.090 967.380 0.860 ;
        RECT 968.540 0.090 990.900 0.860 ;
        RECT 992.060 0.090 1046.900 0.860 ;
        RECT 1048.060 0.090 1078.260 0.860 ;
        RECT 1079.420 0.090 1451.380 0.860 ;
      LAYER Metal3 ;
        RECT 22.330 381.660 1459.790 1462.300 ;
        RECT 22.330 380.500 1459.490 381.660 ;
        RECT 22.330 378.300 1459.790 380.500 ;
        RECT 22.330 377.140 1459.490 378.300 ;
        RECT 22.330 373.820 1459.790 377.140 ;
        RECT 22.330 371.540 1459.490 373.820 ;
        RECT 22.330 363.740 1459.790 371.540 ;
        RECT 22.330 361.460 1459.490 363.740 ;
        RECT 22.330 355.900 1459.790 361.460 ;
        RECT 22.330 353.620 1459.490 355.900 ;
        RECT 22.330 352.540 1459.790 353.620 ;
        RECT 22.330 351.380 1459.490 352.540 ;
        RECT 22.330 346.940 1459.790 351.380 ;
        RECT 22.330 345.780 1459.490 346.940 ;
        RECT 22.330 344.700 1459.790 345.780 ;
        RECT 22.330 342.420 1459.490 344.700 ;
        RECT 22.330 340.220 1459.790 342.420 ;
        RECT 22.330 339.060 1459.490 340.220 ;
        RECT 22.330 337.980 1459.790 339.060 ;
        RECT 22.330 336.820 1459.490 337.980 ;
        RECT 22.330 329.020 1459.790 336.820 ;
        RECT 22.330 327.860 1459.490 329.020 ;
        RECT 22.330 321.180 1459.790 327.860 ;
        RECT 22.330 318.900 1459.490 321.180 ;
        RECT 22.330 316.700 1459.790 318.900 ;
        RECT 22.330 315.540 1459.490 316.700 ;
        RECT 22.330 303.260 1459.790 315.540 ;
        RECT 22.330 302.100 1459.490 303.260 ;
        RECT 22.330 0.140 1459.790 302.100 ;
      LAYER Metal4 ;
        RECT 172.620 30.330 175.540 1451.990 ;
        RECT 177.740 30.330 178.840 1451.990 ;
        RECT 181.040 30.330 329.140 1451.990 ;
        RECT 331.340 30.330 332.440 1451.990 ;
        RECT 334.640 30.330 482.740 1451.990 ;
        RECT 484.940 30.330 486.040 1451.990 ;
        RECT 488.240 30.330 636.340 1451.990 ;
        RECT 638.540 30.330 639.640 1451.990 ;
        RECT 641.840 30.330 789.940 1451.990 ;
        RECT 792.140 30.330 793.240 1451.990 ;
        RECT 795.440 30.330 943.540 1451.990 ;
        RECT 945.740 30.330 946.840 1451.990 ;
        RECT 949.040 30.330 1097.140 1451.990 ;
        RECT 1099.340 30.330 1100.440 1451.990 ;
        RECT 1102.640 30.330 1250.740 1451.990 ;
        RECT 1252.940 30.330 1254.040 1451.990 ;
        RECT 1256.240 30.330 1404.340 1451.990 ;
        RECT 1406.540 30.330 1407.640 1451.990 ;
        RECT 1409.840 30.330 1436.820 1451.990 ;
      LAYER Metal5 ;
        RECT 230.780 1415.650 1436.900 1437.070 ;
        RECT 230.780 1412.350 1436.900 1412.850 ;
        RECT 230.780 1262.470 1436.900 1409.550 ;
        RECT 230.780 1259.170 1436.900 1259.670 ;
        RECT 230.780 1109.290 1436.900 1256.370 ;
        RECT 230.780 1105.990 1436.900 1106.490 ;
        RECT 230.780 956.110 1436.900 1103.190 ;
        RECT 230.780 952.810 1436.900 953.310 ;
        RECT 230.780 802.930 1436.900 950.010 ;
        RECT 230.780 799.630 1436.900 800.130 ;
        RECT 230.780 649.750 1436.900 796.830 ;
        RECT 230.780 646.450 1436.900 646.950 ;
        RECT 230.780 496.570 1436.900 643.650 ;
        RECT 230.780 493.270 1436.900 493.770 ;
        RECT 230.780 343.390 1436.900 490.470 ;
        RECT 230.780 340.090 1436.900 340.590 ;
        RECT 230.780 190.210 1436.900 337.290 ;
        RECT 230.780 186.910 1436.900 187.410 ;
        RECT 230.780 60.530 1436.900 184.110 ;
  END
END asic_top
END LIBRARY

